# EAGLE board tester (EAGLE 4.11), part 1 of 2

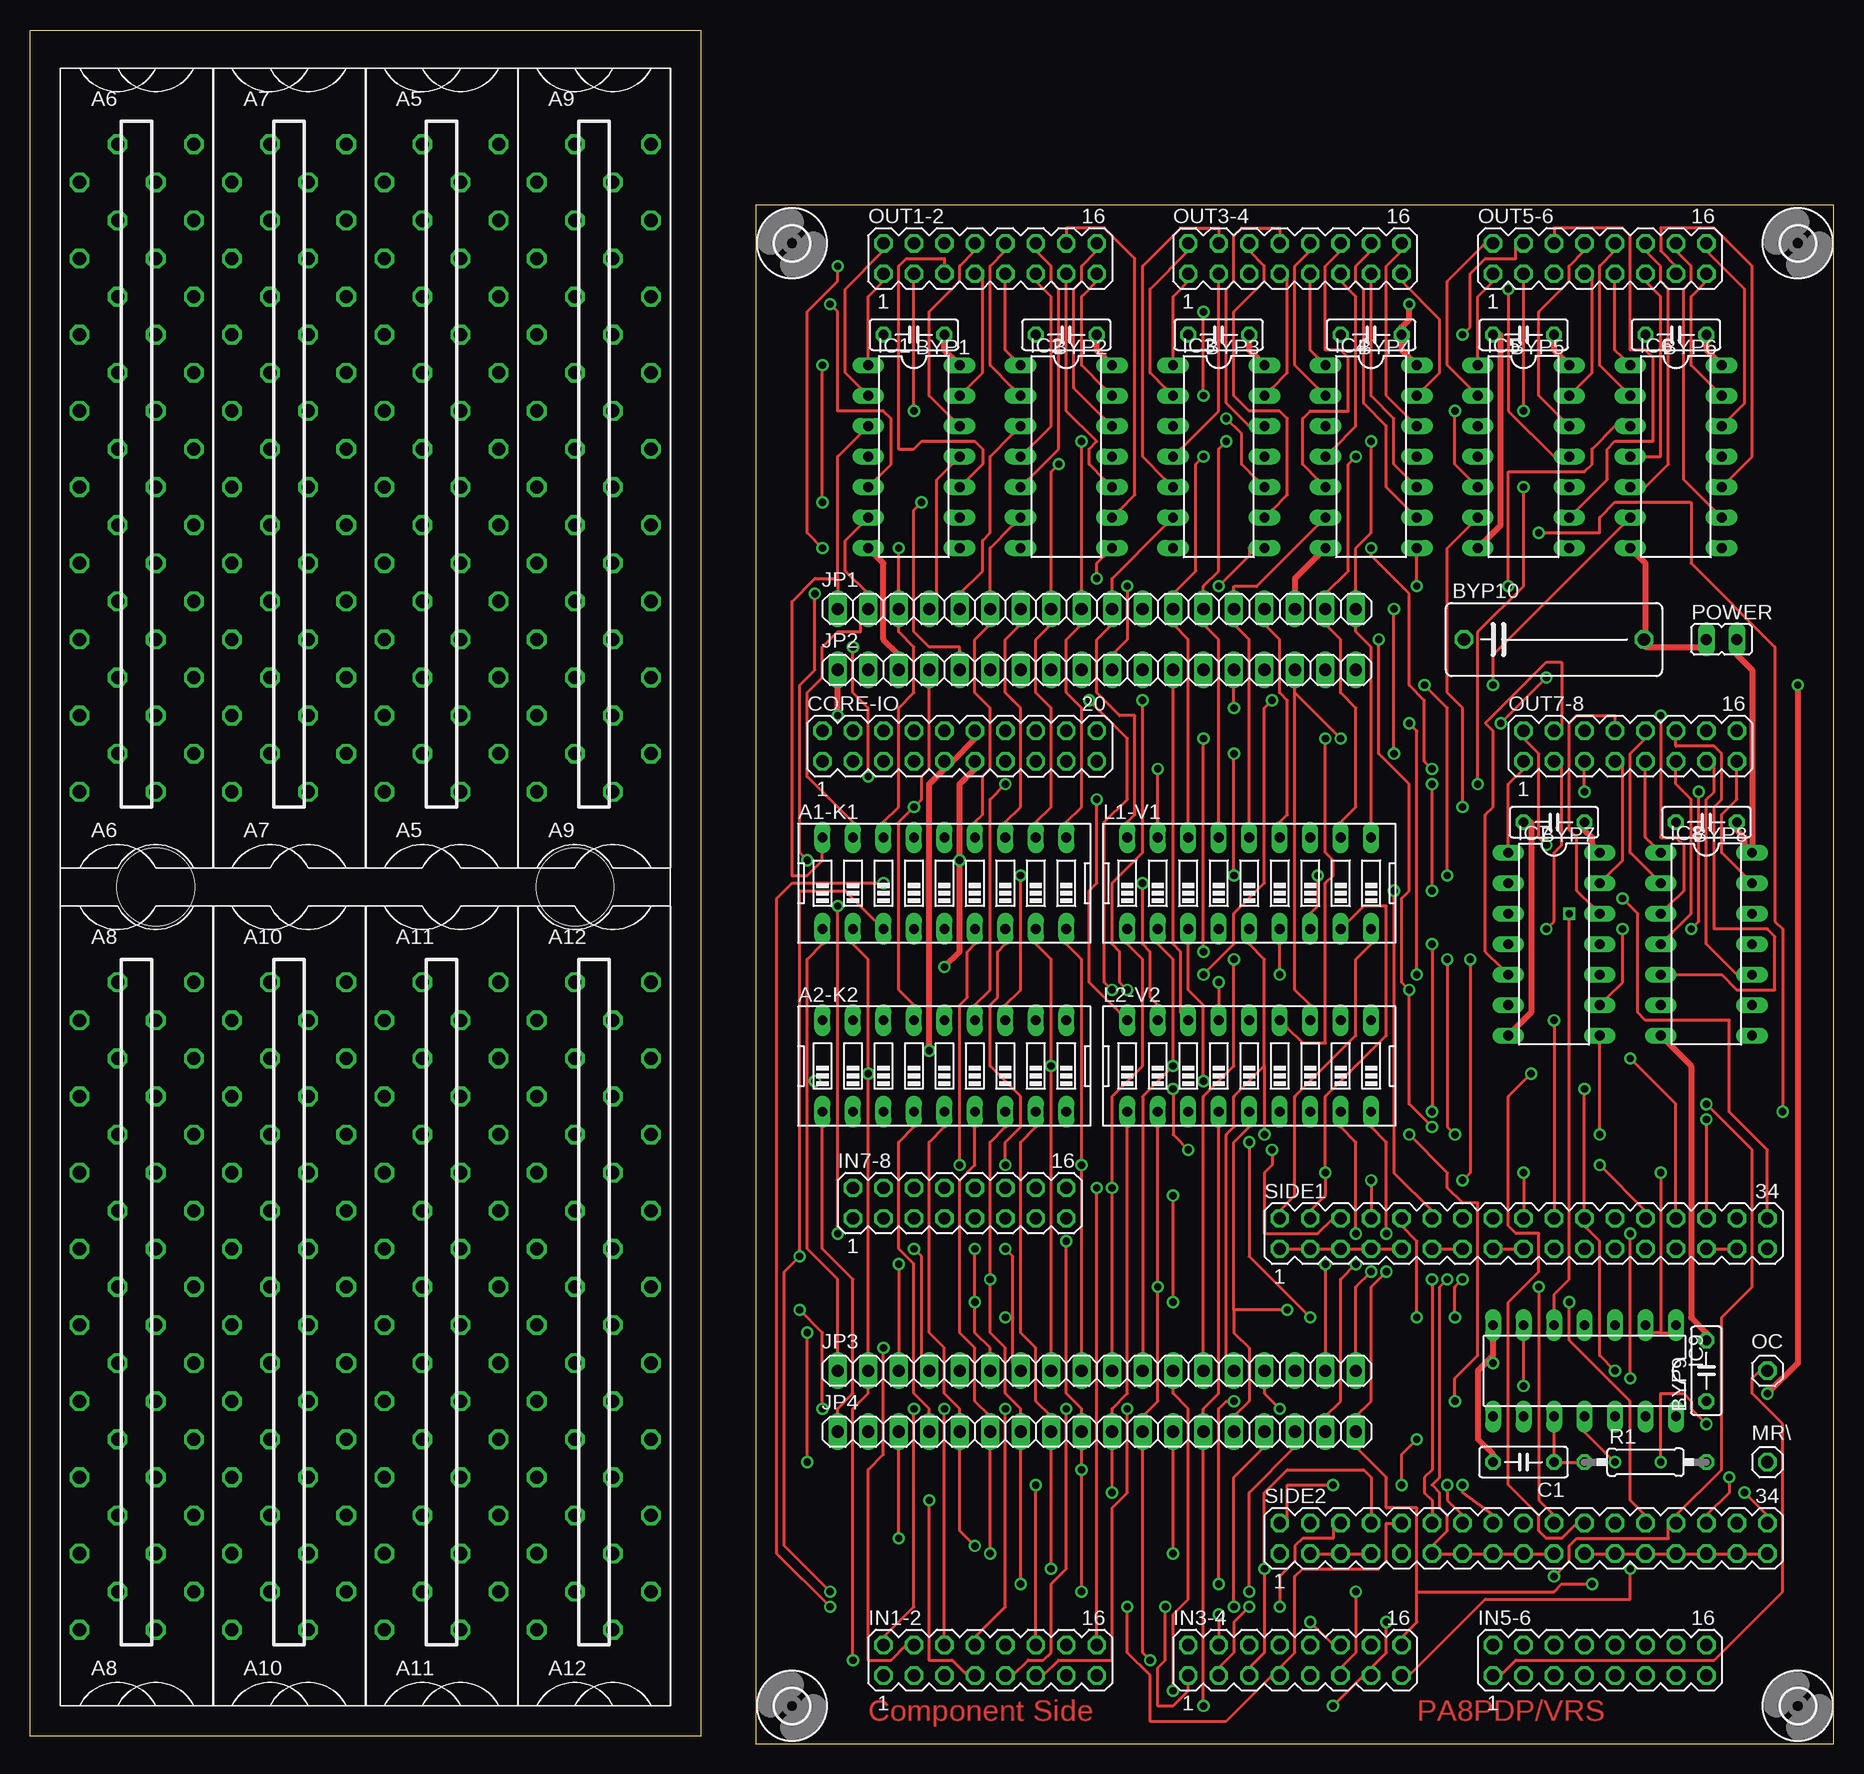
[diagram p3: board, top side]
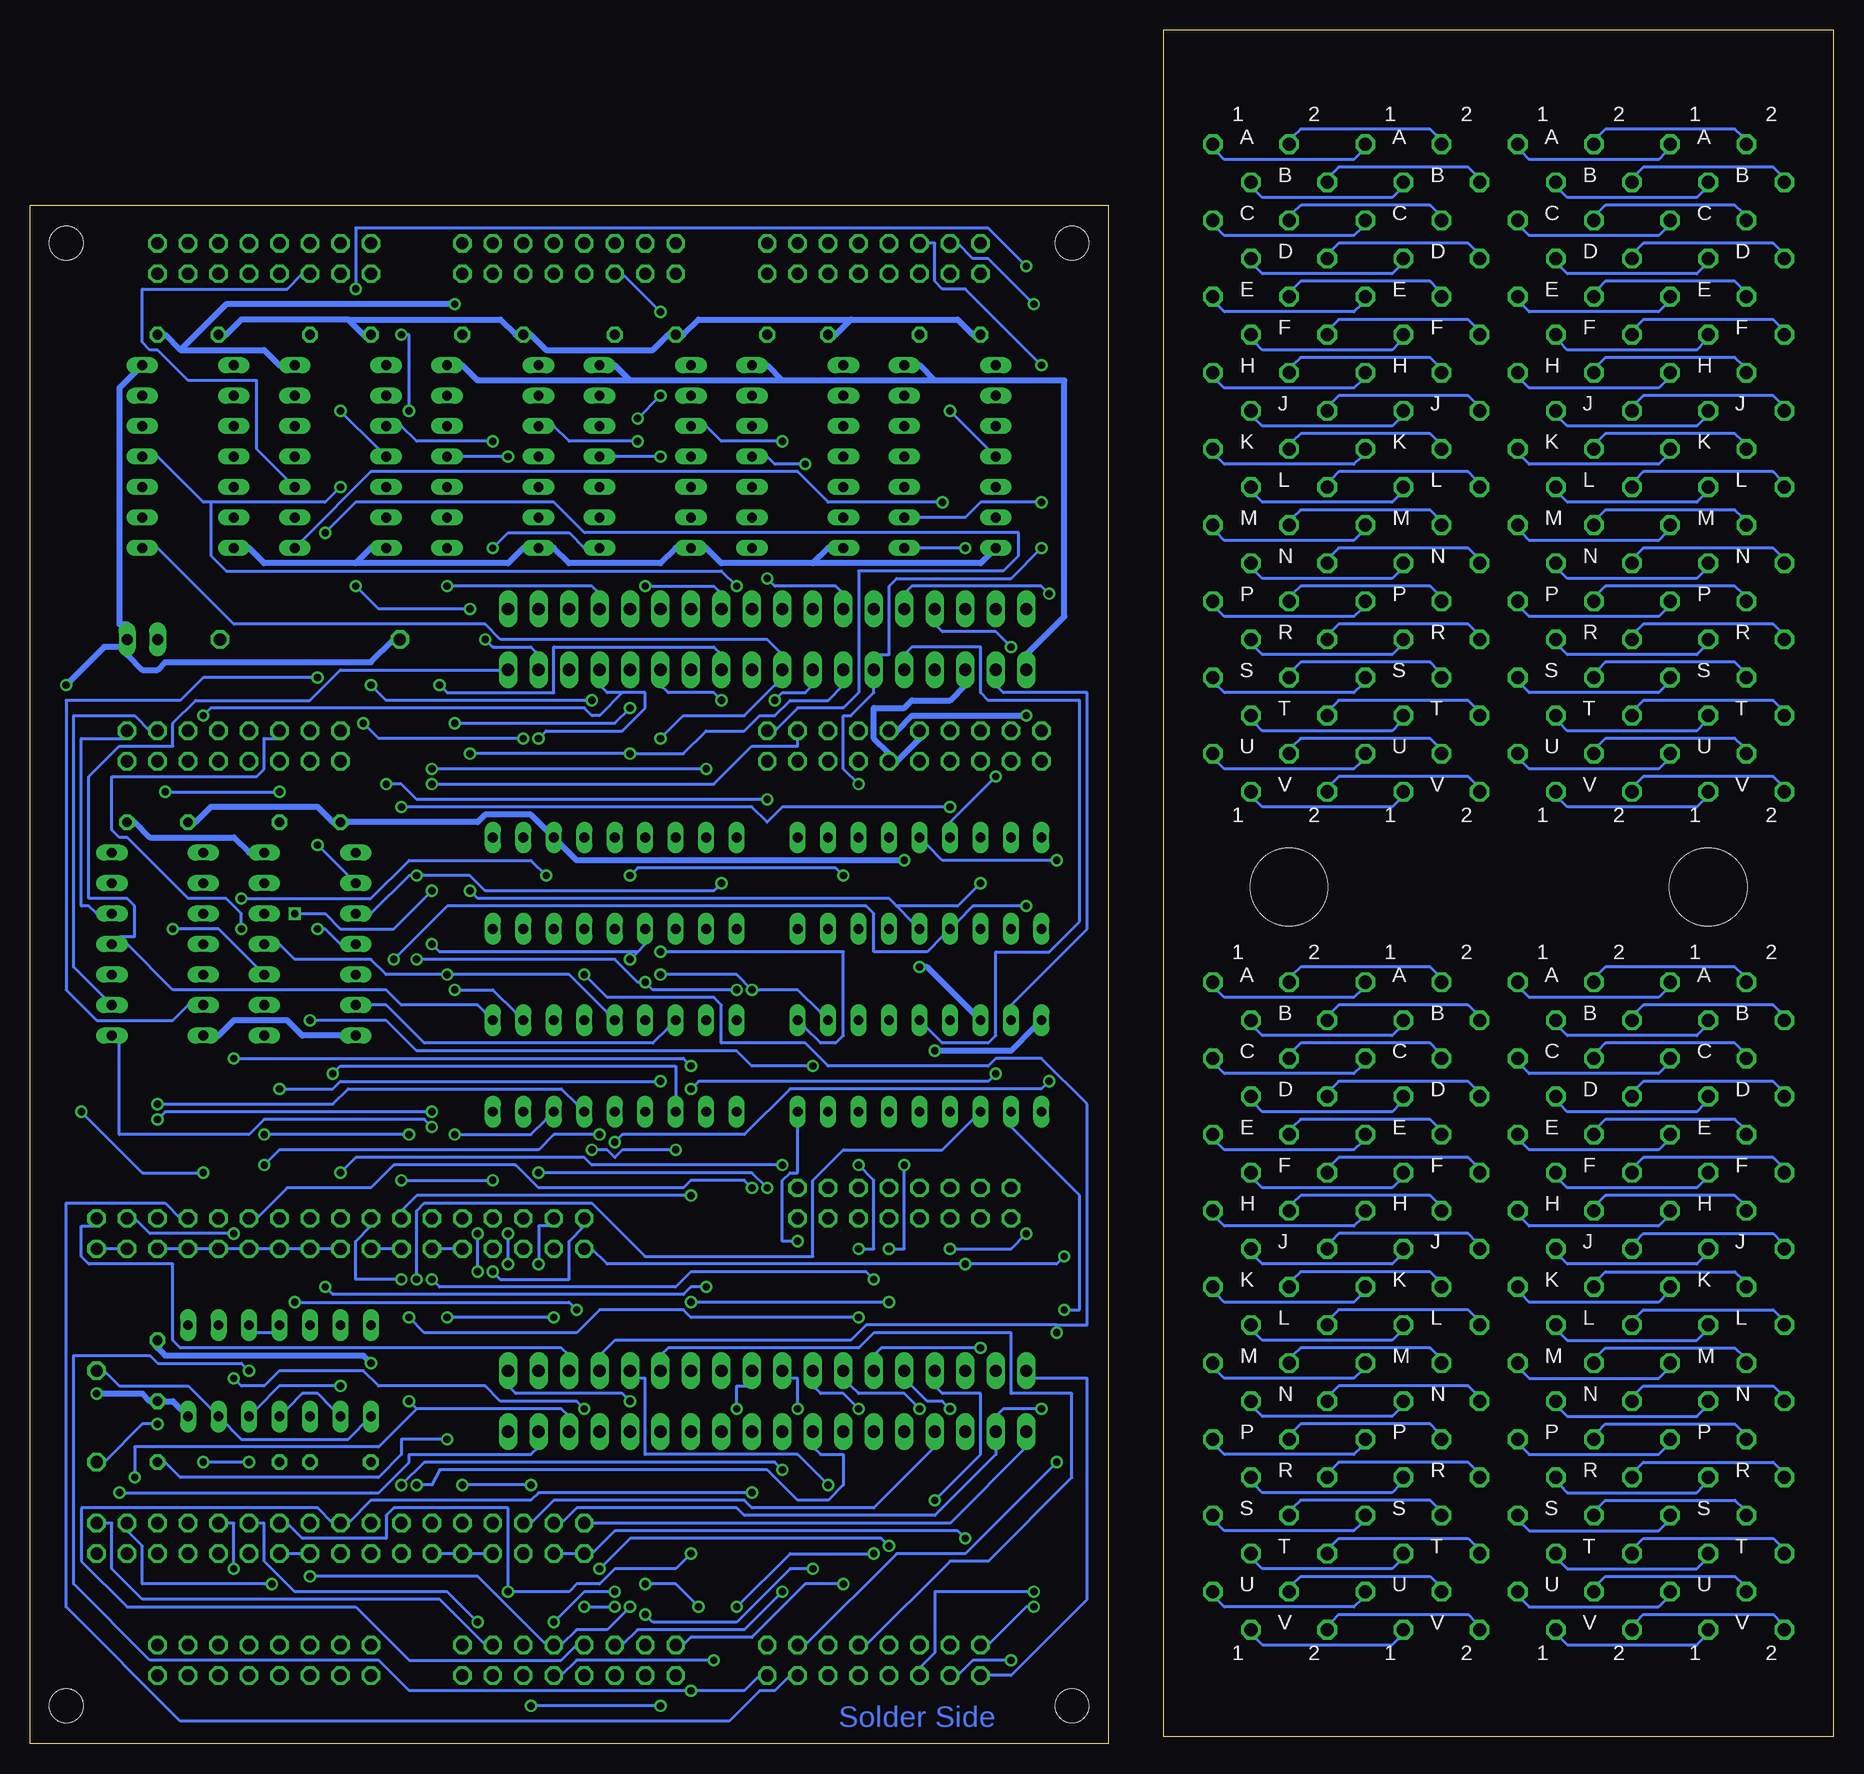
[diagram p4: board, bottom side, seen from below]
Size 150.33 x 142.86 mm. Coordinates in mm from the lower left corner, seen from the top.
Outline: 60.49,128.25 60.49,0 150.33,0 150.33,128.25 60.49,128.25
Outline: 55.88,0.62 0,0.62 0,142.86 55.88,142.86 55.88,0.62
Copper layers (1*16): Top 0.035mm / dielectric 1.5mm / Bottom 0.035mm
Design rules "olimex10mil": minimum track width 10mil, minimum drill 24mil, track to track 10mil, track to pad 10mil, pad to pad 10mil, via to via 10mil, smd to smd 10mil, copper to edge 40mil, drill to drill 10mil, minimum pad ring 10mil, minimum via ring 8mil, stop-mask expansion 0mil, vias tented up to drill 0mil, thermal gap 10mil
Net classes: 1 Power: width 0.508 mm, drill 0.254 mm, clearance 0.254 mm

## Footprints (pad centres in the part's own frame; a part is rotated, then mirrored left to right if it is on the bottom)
EDG-09 = drill 0.813 long: 1 -10.16,-3.81; 2 -7.62,-3.81; 3 -5.08,-3.81; 4 -2.54,-3.81; 5 0,-3.81; 6 2.54,-3.81; 7 5.08,-3.81; 8 7.62,-3.81; 9 10.16,-3.81; 10 10.16,3.81; 11 7.62,3.81; 12 5.08,3.81; 13 2.54,3.81; 14 0,3.81; 15 -2.54,3.81; 16 -5.08,3.81; 17 -7.62,3.81; 18 -10.16,3.81
H807 = drill 1.092 octagon: A1 4.763,28.575; A2 -1.587,28.575; B1 1.587,25.4; B2 -4.763,25.4; C1 4.763,22.225; C2 -1.587,22.225; D1 1.587,19.05; D2 -4.763,19.05; E1 4.763,15.875; E2 -1.587,15.875; F1 1.587,12.7; F2 -4.763,12.7; H1 4.763,9.525; H2 -1.587,9.525; J1 1.587,6.35; J2 -4.763,6.35; K1 4.763,3.175; K2 -1.587,3.175; L1 1.587,0; L2 -4.763,0; M1 4.763,-3.175; M2 -1.587,-3.175; N1 1.587,-6.35; N2 -4.763,-6.35; P1 4.763,-9.525; P2 -1.587,-9.525; R1 1.587,-12.7; R2 -4.763,-12.7; S1 4.763,-15.875; S2 -1.587,-15.875; T1 1.587,-19.05; T2 -4.763,-19.05; U1 4.763,-22.225; U2 -1.587,-22.225; V1 1.587,-25.4; V2 -4.763,-25.4
C050-025X075 = drill 0.813 octagon: 1 -2.54,0; 2 2.54,0
C150-064X183 = drill 1.016 octagon: 1 -7.493,0; 2 7.493,0
MA10-2 = drill 1.016 octagon: 1 -11.43,-1.27; 2 -11.43,1.27; 3 -8.89,-1.27; 4 -8.89,1.27; 5 -6.35,-1.27; 6 -6.35,1.27; 7 -3.81,-1.27; 8 -3.81,1.27; 9 -1.27,-1.27; 10 -1.27,1.27; 11 1.27,-1.27; 12 1.27,1.27; 13 3.81,-1.27; 14 3.81,1.27; 15 6.35,-1.27; 16 6.35,1.27; 17 8.89,-1.27; 18 8.89,1.27; 19 11.43,-1.27; 20 11.43,1.27
DIL14 = drill 0.813 long: 1 -7.62,-3.81; 2 -5.08,-3.81; 3 -2.54,-3.81; 4 0,-3.81; 5 2.54,-3.81; 6 5.08,-3.81; 7 7.62,-3.81; 8 7.62,3.81; 9 5.08,3.81; 10 2.54,3.81; 11 0,3.81; 12 -2.54,3.81; 13 -5.08,3.81; 14 -7.62,3.81
MA08-2 = drill 1.016 octagon: 1 -8.89,-1.27; 2 -8.89,1.27; 3 -6.35,-1.27; 4 -6.35,1.27; 5 -3.81,-1.27; 6 -3.81,1.27; 7 -1.27,-1.27; 8 -1.27,1.27; 9 1.27,-1.27; 10 1.27,1.27; 11 3.81,-1.27; 12 3.81,1.27; 13 6.35,-1.27; 14 6.35,1.27; 15 8.89,-1.27; 16 8.89,1.27
1X18 = drill 1.016 long: 1 -21.59,0; 2 -19.05,0; 3 -16.51,0; 4 -13.97,0; 5 -11.43,0; 6 -8.89,0; 7 -6.35,0; 8 -3.81,0; 9 -1.27,0; 10 1.27,0; 11 3.81,0; 12 6.35,0; 13 8.89,0; 14 11.43,0; 15 13.97,0; 16 16.51,0; 17 19.05,0; 18 21.59,0
1X01 = drill 1.016 octagon: 1 0,0
JP1 = drill 0.914 long: 1 0,-1.27; 2 0,1.27
0207/10 = drill 0.813 octagon: 1 -5.08,0; 2 5.08,0
MA17-2 = drill 1.016 octagon: 1 -20.32,-1.27; 2 -20.32,1.27; 3 -17.78,-1.27; 4 -17.78,1.27; 5 -15.24,-1.27; 6 -15.24,1.27; 7 -12.7,-1.27; 8 -12.7,1.27; 9 -10.16,-1.27; 10 -10.16,1.27; 11 -7.62,-1.27; 12 -7.62,1.27; 13 -5.08,-1.27; 14 -5.08,1.27; 15 -2.54,-1.27; 16 -2.54,1.27; 17 0,-1.27; 18 0,1.27; 19 2.54,-1.27; 20 2.54,1.27; 21 5.08,-1.27; 22 5.08,1.27; 23 7.62,-1.27; 24 7.62,1.27; 25 10.16,-1.27; 26 10.16,1.27; 27 12.7,-1.27; 28 12.7,1.27; 29 15.24,-1.27; 30 15.24,1.27; 31 17.78,-1.27; 32 17.78,1.27; 33 20.32,-1.27; 34 20.32,1.27
2,8 = hole 2.8: 0,0
CBLOCK = hole 6.452: 7.938,68.263; 42.862,68.263

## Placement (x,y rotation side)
A1-K1  A1-K1  [EDG-09]  76.2,71.74 0 top
A2-K2  A2-K2  [EDG-09]  76.2,56.5 0 top
A5  [H807]  34.29,104.76 0 top
A6  [H807]  8.89,104.76 0 top
A7  [H807]  21.59,104.76 0 top
A8  [H807]  8.89,34.91 0 top
A9  [H807]  46.99,104.76 0 top
A10  [H807]  21.59,34.91 0 top
A11  [H807]  34.29,34.91 0 top
A12  [H807]  46.99,34.91 0 top
BYP1  0.1uf  [C050-025X075]  73.66,117.46 180 top
BYP2  0.1uf  [C050-025X075]  86.36,117.46 180 top
BYP3  0.1uf  [C050-025X075]  99.06,117.46 180 top
BYP4  0.1uf  [C050-025X075]  111.76,117.46 180 top
BYP5  0.1uf  [C050-025X075]  124.46,117.46 180 top
BYP6  0.1uf  [C050-025X075]  137.16,117.46 180 top
BYP7  0.1uf  [C050-025X075]  127,76.82 180 top
BYP8  0.1uf  [C050-025X075]  139.7,76.82 180 top
BYP9  0.1uf  [C050-025X075]  139.7,31.1 90 top
BYP10  100uf 25V  [C150-064X183]  127,92.06 0 top
C1  0.1uf  [C050-025X075]  124.46,23.48 180 top
CORE-IO  [MA10-2]  77.47,83.17 0 top
IC1  74LS125N  [DIL14]  73.66,107.3 270 top
IC2  74LS125N  [DIL14]  86.36,107.3 270 top
IC3  74LS125N  [DIL14]  99.06,107.3 270 top
IC4  74LS125N  [DIL14]  111.76,107.3 270 top
IC5  74LS125N  [DIL14]  124.46,107.3 270 top
IC6  74LS125N  [DIL14]  137.16,107.3 270 top
IC7  74LS125N  [DIL14]  127,66.66 270 top
IC8  74LS125N  [DIL14]  139.7,66.66 270 top
IC9  74LS00N  [DIL14]  129.54,31.1 180 top
IN1-2  [MA08-2]  80.01,6.97 0 top
IN3-4  [MA08-2]  105.41,6.97 0 top
IN5-6  [MA08-2]  130.81,6.97 0 top
IN7-8  [MA08-2]  77.47,45.07 0 top
JP1  [1X18]  88.9,94.6 0 top
JP2  [1X18]  88.9,89.52 0 top
JP3  [1X18]  88.9,31.1 0 top
JP4  [1X18]  88.9,26.02 0 top
L1-V1  L1-V1  [EDG-09]  101.6,71.74 0 top
L2-V2  L2-V2  [EDG-09]  101.6,56.5 0 top
MR\  MR\  [1X01]  144.78,23.48 0 top
OC  OC  [1X01]  144.78,31.1 0 top
OUT1-2  [MA08-2]  80.01,123.81 0 top
OUT3-4  [MA08-2]  105.41,123.81 0 top
OUT5-6  [MA08-2]  130.81,123.81 0 top
OUT7-8  [MA08-2]  133.35,83.17 0 top
POWER  POWER  [JP1]  140.97,92.06 270 top
R1  1K  [0207/10]  134.62,23.48 0 top
SIDE1  [MA17-2]  124.46,42.53 0 top
SIDE2  [MA17-2]  124.46,17.13 0 top
U$1  [2,8]  63.5,3.16 270 top
U$2  [2,8]  147.32,3.16 270 top
U$3  [2,8]  147.32,125.08 270 top
U$4  [2,8]  63.5,125.08 270 top
U$5  [CBLOCK]  2.54,3.16 0 top

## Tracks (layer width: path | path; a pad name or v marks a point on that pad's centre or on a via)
A1  (via drill 0.61)
  Top 0.254: 64.77,55.23 64.77,41.26 67.31,38.72 67.31,32.37 JP3.1 | 64.77,55.23 64.77,65.39 66.04,66.66 A1-K1.1 | v115.57,35.55 115.57,41.89 114.3,43.16 SIDE1.10 | v106.68,35.55 101.6,40.62 v101.6,50.15 | 64.77,55.23 v65.41,55.23
  Bottom 0.254: IN1-2.1 70.48,5.7 68.58,5.7 62.23,12.05 62.23,30.46 66.67,30.46 JP3.1 | v106.68,35.55 v115.57,35.55 | v101.6,50.15 100.97,50.78 90.81,50.78 87,54.59 66.04,54.59 v65.41,55.23
A2  (via drill 0.61)
  Top 0.254: A2-K2.1 66.04,51.42 66.04,41.26 68.58,38.72 68.58,29.2 67.31,27.92 67.31,27.29 JP4.1 | v115.57,25.38 114.3,24.11 v114.3,21.57 | v108.59,21.57 104.78,21.57 104.78,18.4 SIDE2.2
  Bottom 0.254: SIDE2.2 103.5,18.4 73.66,18.4 67.31,24.75 JP4.1 | v115.57,25.38 119.38,25.38 119.38,24.11 121.28,22.21 137.8,22.21 139.06,23.48 R1.2 | v108.59,21.57 v114.3,21.57
B1  (via drill 0.61)
  Top 0.254: A1-K1.2 68.58,66.66 69.85,65.39 v69.85,55.87 69.85,32.37 JP3.2 69.85,29.83 69.85,29.2 68.58,27.92 v68.58,6.97 | v103.5,49.52 103.5,48.24 102.87,47.61 102.87,42.53 107.31,42.53 108.59,43.8 SIDE1.6 | v96.52,49.52 95.25,50.78 v95.25,54.59
  Bottom 0.254: v68.58,6.97 71.75,6.97 73.03,5.7 IN1-2.3 | v96.52,49.52 100.97,49.52 101.6,48.88 102.23,49.52 v103.5,49.52 | v95.25,54.59 94.62,55.23 70.48,55.23 v69.85,55.87
B2  (via drill 0.61)
  Top 0.254: v64.14,36.18 66.04,34.27 v66.04,27.92
  Bottom 0.254: v64.14,36.18 62.87,36.18 62.87,45.7 68.58,51.42 A2-K2.2 | v66.04,27.92 69.22,27.92 69.85,27.29 JP4.2 69.85,24.75 69.85,24.11 74.93,19.04 90.81,19.04 91.44,19.67 104.78,19.67 106.05,18.4 SIDE2.4
C1  (via drill 0.61)
  Top 0.254: A1-K1.3 70.48,68.57 67.95,71.11 64.14,71.11 v64.14,40.62 62.87,39.35 62.87,16.49 v66.67,12.68 | v72.39,39.99 72.39,32.37 JP3.3 | SIDE1.1 104.78,41.26 106.05,41.26 SIDE1.3 107.31,41.26 108.59,41.26 SIDE1.5 109.86,41.26 111.12,41.26 SIDE1.7 112.4,41.26 113.66,41.26 SIDE1.9 | SIDE1.13 118.75,41.26 117.47,41.26 SIDE1.11 | SIDE1.17 123.83,41.26 122.56,41.26 SIDE1.15 | SIDE1.31 141.61,41.26 140.34,41.26 SIDE1.29
  Bottom 0.254: v64.14,40.62 64.77,39.99 v72.39,39.99 102.23,39.99 103.5,41.26 SIDE1.1 | v66.67,12.68 74.93,12.68 74.93,7.6 76.2,6.33 IN1-2.5 | SIDE1.11 116.2,41.26 114.94,41.26 SIDE1.9 | SIDE1.15 121.28,41.26 120.02,41.26 SIDE1.13 | SIDE1.17 125.09,41.26 126.36,41.26 SIDE1.19 127.64,41.26 128.91,41.26 SIDE1.21 130.18,41.26 131.44,41.26 SIDE1.23 132.72,41.26 133.99,41.26 SIDE1.25 135.25,41.26 136.53,41.26 SIDE1.27 137.8,41.26 139.06,41.26 SIDE1.29 | SIDE1.33 144.14,41.26 142.88,41.26 SIDE1.31
C2  (via drill 0.61)
  Top 0.254: SIDE2.3 107.31,15.86 108.59,15.86 SIDE2.5 109.86,15.86 111.12,15.86 SIDE2.7 | v72.39,17.13 72.39,24.75 JP4.3 | v118.11,38.72 117.47,38.09 117.47,22.21 116.84,21.57 117.47,20.94 117.47,19.67 118.11,19.04 118.11,17.77 116.84,16.49 SIDE2.11 117.47,15.86 118.75,15.86 SIDE2.13 120.02,15.86 121.28,15.86 SIDE2.15 122.56,15.86 123.83,15.86 SIDE2.17 125.09,15.86 126.36,15.86 SIDE2.19 | SIDE2.21 130.18,15.86 131.44,15.86 SIDE2.23 132.72,15.86 133.99,15.86 SIDE2.25 135.25,15.86 136.53,15.86 SIDE2.27 137.8,15.86 139.06,15.86 SIDE2.29 140.34,15.86 141.61,15.86 SIDE2.31 142.88,15.86 144.14,15.86 SIDE2.33
  Bottom 0.254: SIDE2.3 106.05,15.86 104.78,15.86 SIDE2.1 103.5,15.86 101.6,17.77 73.03,17.77 v72.39,17.13 | SIDE2.7 112.4,15.86 113.66,15.86 SIDE2.9 114.94,15.86 116.2,15.86 SIDE2.11 | v118.11,38.72 118.11,44.44 117.47,45.07 103.5,45.07 99.06,40.62 85.09,40.62 85.09,46.98 82.55,49.52 74.3,49.52 71.75,52.05 A2-K2.3 | SIDE2.21 128.91,15.86 127.64,15.86 SIDE2.19
D1  (via drill 0.61)
  Top 0.254: v67.31,42.53 v67.31,69.84 | v73.66,41.26 74.3,40.62 74.3,31.73 JP3.4 | v74.93,20.3 74.93,6.97 76.84,6.97 78.11,5.7 IN1-2.7 | v111.76,46.98 111.76,44.44 SIDE1.8 | v119.38,46.98 120.02,47.61 v120.02,65.39
  Bottom 0.254: v67.31,69.84 71.75,69.84 73.03,68.57 A1-K1.4 74.3,67.3 75.56,66.03 80.01,66.03 80.01,69.2 80.65,69.84 115.57,69.84 v120.02,65.39 | v67.31,42.53 68.58,41.26 v73.66,41.26 | v74.93,20.3 71.12,24.11 71.12,29.2 74.3,29.2 74.93,29.83 JP3.4 | v119.38,46.98 v111.76,46.98
D2  (via drill 0.61)
  Top 0.254: v101.6,11.41 100.33,10.14 100.33,7.6 99.06,6.33 IN3-4.3 | v104.14,11.41 104.14,13.95 105.41,15.22 105.41,16.49 106.05,17.13 108.59,17.13 108.59,18.4 SIDE2.6 | A2-K2.4 73.66,51.42 72.39,50.15 72.39,41.26 73.66,39.99 73.66,29.2 74.93,27.92 74.93,27.29 JP4.4
  Bottom 0.254: v104.14,11.41 v101.6,11.41 | SIDE2.6 108.59,18.4 106.68,20.3 90.81,20.3 90.17,19.67 80.01,19.67 74.93,24.75 JP4.4
E1  (via drill 0.61)
  Top 0.254: v73.66,27.92 73.66,11.41 71.12,8.88 IN1-2.2 | v113.66,71.11 113.66,47.61 116.84,44.44 SIDE1.12 | v66.67,11.41 62.23,15.86 62.23,70.47 63.5,71.74 v71.12,71.74
  Bottom 0.254: v73.66,27.92 74.3,28.56 75.56,28.56 76.84,29.83 77.47,29.83 JP3.5 | 78.11,69.84 78.74,70.47 113.03,70.47 v113.66,71.11 | 78.11,69.84 76.84,68.57 A1-K1.5 | v66.67,11.41 67.31,11.41 70.48,8.24 IN1-2.2 | v71.12,71.74 73.03,69.84 78.11,69.84
E2  (via drill 0.61)
  Top 0.254: IN3-4.5 101.6,6.33 102.87,7.6 v102.87,14.59 102.87,20.3 102.87,20.94 104.78,22.84 111.12,22.84 111.76,22.21 111.76,19.04 SIDE2.8 | A2-K2.5 76.2,51.42 74.93,50.15 74.93,34.27 76.2,33.01 76.2,29.2 77.47,27.92 77.47,27.29 JP4.5 77.47,24.75 77.47,17.77 v78.74,16.49
  Bottom 0.254: v102.87,14.59 100.33,17.13 79.38,17.13 v78.74,16.49
F1  (via drill 0.61)
  Top 0.254: v77.47,48.24 77.47,61.58 78.11,62.21 78.11,66.03 78.74,66.66 A1-K1.6 | v78.74,41.26 v78.74,36.81 78.74,34.27 80.01,33.01 80.01,32.37 JP3.6 | v71.12,33.01 71.12,24.11 69.85,22.84 69.85,6.97 71.75,6.97 73.03,8.24 IN1-2.4 | v95.25,36.81 v95.25,45.7
  Bottom 0.254: v77.47,48.24 77.47,41.26 v78.74,41.26 | v71.12,33.01 79.38,33.01 80.01,32.37 JP3.6 | v95.25,45.7 118.11,45.7 119.38,44.44 SIDE1.14 | v78.74,36.81 v95.25,36.81
F2  (via drill 0.61)
  Top 0.254: SIDE2.10 113.66,18.4 113.03,18.4 113.03,15.22 112.4,14.59 106.05,14.59 105.41,13.95 105.41,7.6 104.14,6.33 IN3-4.7 103.5,5.7 99.69,1.89 93.34,1.89 93.34,5.7 91.44,7.6 v91.44,11.41 | A2-K2.6 78.74,51.42 78.74,48.24 77.47,46.98 77.47,34.27 78.74,33.01 78.74,28.56 80.01,27.29 JP4.6 80.01,24.75 v80.01,15.86
  Bottom 0.254: v91.44,11.41 87,15.86 v80.01,15.86
GND  (via drill 0.61)
  Top 0.508: 121.28,31.73 121.92,32.37 121.92,33.64 IC9.7 | 121.28,31.73 120.65,31.1 120.65,25.38 121.92,24.11 C1.2 | IC7.7 123.83,59.68 125.09,60.95 125.09,76.82 BYP7.2 | BYP9.2 139.7,34.27 138.43,35.55 138.43,56.5 136.53,58.41 IC8.7 | v121.92,31.73 121.28,31.73 | v76.2,64.76 77.47,66.03 v77.47,73.65 77.47,80 78.74,81.27 CORE-IO.11 | IC1.7 70.48,99.05 71.12,98.41 71.12,92.06 72.39,90.79 JP2.3 | IC4.7 107.31,99.05 105.41,97.14 105.41,95.87 JP1.16 | IC6.7 133.99,99.05 134.62,98.41 134.62,92.7 BYP10.2 134.62,91.43 139.06,91.43 POWER.1 | IC5.7 121.28,100.32 122.56,101.59 122.56,117.46 BYP5.2
  Bottom 0.508: L1-V1.12 107.31,76.19 | IC8.7 134.62,59.04 133.35,60.31 128.91,60.31 127.64,59.04 124.46,59.04 IC7.7 | BYP8.2 136.53,76.82 135.25,78.09 126.36,78.09 125.09,76.82 BYP7.2 123.83,76.82 113.03,76.82 112.4,77.46 108.59,77.46 107.31,76.19 | v121.92,31.73 122.56,32.37 139.06,32.37 139.7,33.01 BYP9.2 | v76.2,64.76 75.56,64.76 71.75,60.95 A2-K2.16 | CORE-IO.10 76.2,83.81 78.11,81.9 CORE-IO.11 78.74,82.54 80.01,83.81 80.01,86.35 77.47,86.35 76.84,86.98 73.66,86.98 72.39,88.25 JP2.3 | 85.09,98.41 83.82,99.68 IC2.7 | 85.09,98.41 92.71,98.41 93.98,99.68 IC3.7 96.52,99.68 97.79,98.41 105.41,98.41 106.68,99.68 IC4.7 109.22,99.68 110.49,98.41 123.19,98.41 | 85.09,98.41 71.12,98.41 70.48,99.05 IC1.7 | 81.92,118.73 73.03,118.73 71.75,117.46 BYP1.2 | 81.92,118.73 83.19,117.46 BYP2.2 | 81.92,118.73 94.62,118.73 95.89,117.46 BYP3.2 97.16,117.46 98.43,116.19 107.31,116.19 108.59,117.46 BYP4.2 109.86,117.46 111.12,118.73 123.83,118.73 | 123.83,118.73 132.72,118.73 133.99,117.46 BYP6.2 | 123.83,118.73 122.56,117.46 BYP5.2 | 123.19,98.41 130.81,98.41 132.08,99.68 IC6.7 | 123.19,98.41 121.92,99.68 IC5.7 | v77.47,73.65 104.78,73.65 106.05,74.92 L1-V1.12 | L1-V1.12 107.31,76.19
H1  (via drill 0.61)
  Top 0.254: v81.28,48.24 81.28,50.15 82.55,51.42 82.55,53.96 80.01,56.5 80.01,61.58 80.65,62.21 80.65,66.03 81.28,66.66 A1-K1.7 | v81.28,41.26 81.92,40.62 81.92,35.55 | 81.92,35.55 81.92,31.73 JP3.7 | v76.2,27.92 76.2,8.88 IN1-2.6 | v119.38,38.72 118.75,38.09 v118.75,35.55 | 81.92,35.55 v81.28,35.55
  Bottom 0.254: v81.28,48.24 80.01,46.98 80.01,41.26 v81.28,41.26 | v76.2,27.92 77.47,29.2 81.28,29.2 81.92,29.83 82.55,29.83 JP3.7 | v119.38,38.72 123.19,38.72 123.19,41.89 121.92,43.16 SIDE1.16 | v118.75,35.55 117.47,34.27 104.78,34.27 102.87,36.18 95.89,36.18 95.25,35.55 v81.28,35.55
H2  (via drill 0.61)
  Top 0.254: A2-K2.7 81.28,51.42 80.01,50.15 v80.01,38.72 80.01,34.27 81.28,33.01 81.28,29.2 82.55,27.92 82.55,27.29 JP4.7 82.55,24.75 v82.55,13.32 | v116.84,38.72 116.84,22.84 116.2,22.21 116.2,20.94 116.84,20.3 116.84,19.04 SIDE2.12
  Bottom 0.254: v82.55,13.32 85.72,13.32 90.17,8.88 95.25,8.88 95.89,8.24 IN3-4.2 | v116.84,38.72 116.2,38.09 96.52,38.09 95.25,39.35 80.65,39.35 v80.01,38.72
J1  (via drill 0.61)
  Top 0.254: A1-K1.8 83.82,66.66 85.09,65.39 v85.09,56.5 85.09,32.37 JP3.8 | v81.28,27.92 81.28,11.41 78.74,8.88 IN1-2.8 | v127,60.31 127,44.44 SIDE1.20
  Bottom 0.254: v81.28,27.92 82.55,29.2 84.45,29.2 85.09,29.83 JP3.8 | v127,60.31 120.65,60.31 118.11,57.77 91.44,57.77 90.17,56.5 v85.09,56.5
J2  (via drill 0.61)
  Top 0.254: A2-K2.8 83.82,51.42 82.55,50.15 82.55,34.27 83.82,33.01 83.82,28.56 85.09,27.29 JP4.8 85.09,24.75 v85.09,14.59 | v99.06,10.78 99.06,8.88 IN3-4.4 | v118.11,21.57 118.11,20.3 119.38,19.04 SIDE2.14
  Bottom 0.254: v99.06,10.78 98.43,10.14 91.44,10.14 87,14.59 v85.09,14.59 | v118.11,21.57 116.84,21.57 116.2,22.84 88.9,22.84 86.36,20.3 83.82,20.3 82.55,21.57 82.55,24.11 84.45,24.11 85.09,24.75 JP4.8
K1  (via drill 0.61)
  Top 0.254: v86.36,27.92 86.36,14.59 85.09,13.32 85.09,7.6 84.45,6.97 83.19,6.97 81.92,5.7 IN1-2.9 | A1-K1.9 86.36,66.66 87.63,65.39 v87.63,48.24 87.63,32.37 JP3.9 | v124.46,47.61 124.46,44.44 SIDE1.18
  Bottom 0.254: v86.36,27.92 86.36,30.46 87,30.46 JP3.9 | v124.46,47.61 123.19,48.88 104.14,48.88 103.5,48.24 v87.63,48.24
K2  (via drill 0.61)
  Top 0.254: v86.36,41.89 86.36,29.2 87.63,27.92 87.63,27.29 JP4.9 87.63,24.75 v87.63,22.84 v87.63,12.68 | v119.38,21.57 119.38,20.94 121.92,19.04 SIDE2.16
  Bottom 0.254: v86.36,41.89 87.63,41.89 87.63,46.98 87,47.61 86.36,47.61 86.36,51.42 A2-K2.9 | v87.63,12.68 90.81,9.51 99.69,9.51 100.97,8.24 IN3-4.6 | v87.63,22.84 88.27,23.48 117.47,23.48 v119.38,21.57
L1  (via drill 0.61)
  Top 0.254: L1-V1.1 91.44,66.66 92.71,65.39 92.71,56.5 90.17,53.96 v90.17,46.34 90.17,32.37 JP3.10 | v91.44,27.92 91.44,20.94 90.17,19.67 90.17,6.97 85.72,6.97 84.45,5.7 IN1-2.11
  Bottom 0.254: v91.44,27.92 91.44,29.83 90.17,29.83 JP3.10 | v90.17,46.34 90.81,46.98 95.25,46.98 95.89,46.34 107.95,46.34 109.86,48.24 120.02,48.24 121.92,46.34 128.91,46.34 131.44,43.8 SIDE1.24
L2  (via drill 0.61)
  Top 0.254: L2-V2.1 91.44,29.2 90.17,27.92 JP4.10 v90.17,20.94
  Bottom 0.254: IN3-4.8 104.78,8.24 106.05,6.97 118.75,6.97 123.19,11.41 142.24,11.41 146.05,15.22 146.05,19.67 126.36,19.67 125.09,18.4 SIDE2.18 123.83,18.4 121.92,20.3 108.59,20.3 107.95,20.94 v90.17,20.94
M1  (via drill 0.61)
  Top 0.254: L1-V1.2 93.98,66.66 95.25,65.39 v95.25,56.5 92.71,53.96 92.71,32.37 JP3.11 | v133.35,57.13 137.16,53.32 137.16,44.44 SIDE1.28
  Bottom 0.254: IN1-2.13 87,5.7 88.27,4.43 89.53,4.43 92.08,1.89 137.8,1.89 147.32,11.41 147.32,45.07 139.06,45.07 137.8,43.8 SIDE1.28 | v95.25,56.5 95.89,57.13 v133.35,57.13
M2  (via drill 0.61)
  Top 0.254: L2-V2.2 93.98,51.42 v93.98,38.09 93.98,28.56 92.71,27.29 JP4.11 92.71,24.75 92.71,7.6 v93.34,6.97 | v125.73,38.09 125.73,20.3 127,19.04 SIDE2.20
  Bottom 0.254: v93.34,6.97 104.78,6.97 106.05,5.7 IN3-4.9 | v125.73,38.09 125.09,37.45 95.89,37.45 95.25,38.09 v93.98,38.09
MR\  (via drill 0.61)
  Top 0.254: v139.7,26.65 138.43,27.92 138.43,28.56 137.8,29.2 135.89,29.2 v135.89,23.48 | v132.08,23.48 129.54,26.02 IC9.11
  Bottom 0.254: IC9.9 125.09,27.92 126.36,29.2 127.64,29.2 128.91,27.92 IC9.11 | v139.7,26.65 140.97,26.65 144.14,23.48 MR\.1 | v132.08,23.48 v135.89,23.48
N1  (via drill 0.61)
  Top 0.254: v95.25,4.43 95.25,10.78 96.52,12.05 96.52,27.92 95.25,29.2 95.25,29.83 JP3.12 | v97.79,55.23 97.79,61.58 96.52,62.85 96.52,66.66 L1-V1.3 | v129.54,54.59 129.54,53.32 129.54,44.44 SIDE1.22 129.54,43.16 130.81,41.89 130.81,32.37 v132.08,31.1
  Bottom 0.254: IN1-2.15 89.53,5.7 90.81,4.43 v95.25,4.43 118.75,4.43 121.28,6.97 140.34,6.97 146.69,13.32 146.69,32.37 140.34,32.37 139.7,31.73 132.72,31.73 v132.08,31.1 | v97.79,55.23 124.46,55.23 125.09,54.59 v129.54,54.59
N2  (via drill 0.61)
  Top 0.254: v125.09,55.87 123.19,53.96 123.19,43.16 123.83,42.53 125.73,42.53 125.73,39.35 123.19,36.81 123.19,21.57 125.73,19.04 125.73,17.77 126.36,17.13 127.64,17.13 128.91,18.4 SIDE2.22 | v110.49,12.68 110.49,7.6 109.22,6.33 IN3-4.11 | v95.25,15.86 95.25,24.75 JP4.12
  Bottom 0.254: v125.09,55.87 124.46,56.5 96.52,56.5 96.52,53.96 L2-V2.3 | SIDE2.22 128.91,18.4 127.64,17.13 120.65,17.13 120.65,19.04 120.02,19.67 110.49,19.67 v110.49,12.68 105.41,12.68 104.78,13.32 102.87,13.32 101.6,14.59 96.52,14.59 v95.25,15.86
N$1  (via drill 0.61)
  Top 0.254: v124.46,29.83 124.46,33.64 IC9.6
  Bottom 0.254: v124.46,29.83 129.54,29.83 131.44,27.92 IC9.12
N$2
  Bottom 0.254: IC9.4 130.18,34.27 131.44,34.27 IC9.3
N$5
  Top 0.254: R1.1 128.91,23.48 127.64,23.48 C1.1 127,24.11 127,26.02 IC9.10
N$26
  Bottom 0.254: A5.L1 36.2,104.12 36.83,103.49 47.62,103.49 48.26,104.12 A9.L1
N$33
  Bottom 0.254: A5.L2 29.85,105.4 30.48,106.03 41.28,106.03 41.91,105.4 A9.L2
N$34
  Bottom 0.254: A5.M1 39.37,100.95 40.01,100.32 50.8,100.32 51.44,100.95 A9.M1
N$35
  Bottom 0.254: A5.M2 33.02,102.22 33.66,102.86 44.45,102.86 45.09,102.22 A9.M2
N$36
  Bottom 0.254: A5.N1 36.2,97.78 36.83,97.14 47.62,97.14 48.26,97.78 A9.N1
N$49
  Bottom 0.254: A5.N2 29.85,99.05 30.48,99.68 41.28,99.68 41.91,99.05 A9.N2
N$50
  Bottom 0.254: A5.P1 39.37,94.6 40.01,93.97 50.8,93.97 51.44,94.6 A9.P1
N$51
  Bottom 0.254: A5.P2 33.02,95.87 33.66,96.51 44.45,96.51 45.09,95.87 A9.P2
N$52
  Bottom 0.254: A5.R1 36.2,91.43 36.83,90.79 47.62,90.79 48.26,91.43 A9.R1
N$53
  Top 0.254: IC1.1 69.85,115.56 69.85,120.64 71.12,121.91 OUT1-2.1
N$54  (via drill 0.61)
  Top 0.254: v73.66,111.11 73.66,121.91 OUT1-2.3
  Bottom 0.254: v73.66,111.11 70.48,107.94 IC1.4
N$55
  Top 0.254: IC1.10 78.11,105.4 79.38,106.67 79.38,107.94 78.74,108.57 74.3,108.57 73.66,107.94 72.39,107.94 72.39,123.18 73.03,123.81 76.2,123.81 76.2,123.18 OUT1-2.5
N$56
  Top 0.254: IC1.13 78.11,113.02 79.38,114.29 79.38,122.54 OUT1-2.7
N$57
  Top 0.254: IC1.2 69.22,113.02 67.95,114.29 67.95,121.27 71.12,124.45 OUT1-2.2
N$58  (via drill 0.61)
  Top 0.254: v66.67,120 67.31,119.37 67.31,111.11 71.12,111.11 71.75,110.48 71.75,106.67 70.48,105.4 IC1.5
  Bottom 0.254: v66.67,120 70.48,123.81 71.75,123.81 73.03,125.08 OUT1-2.4
N$59  (via drill 0.61)
  Top 0.254: v66.04,103.49 v66.04,114.92
  Bottom 0.254: v66.04,103.49 71.12,103.49 72.39,102.22 76.2,102.22 IC1.9 | v66.04,114.92 72.39,121.27 74.3,121.27 74.93,121.91 74.93,125.08 75.56,125.08 OUT1-2.6
N$60
  Top 0.254: IC1.12 76.84,110.48 74.93,112.38 74.93,119.37 77.47,121.91 77.47,123.18 78.74,124.45 OUT1-2.8
N$61  (via drill 0.61)
  Top 0.254: v124.46,111.11 124.46,121.91 OUT5-6.3
  Bottom 0.254: v124.46,111.11 121.28,107.94 IC5.4
N$62
  Top 0.254: IC2.10 89.53,105.4 88.27,106.67 88.27,107.94 88.9,108.57 86.36,111.11 86.36,121.91 OUT1-2.13
N$63
  Top 0.254: IC2.4 83.19,107.94 85.09,109.84 85.09,120.64 83.82,121.91 OUT1-2.11
N$64
  Top 0.254: IC2.1 81.92,115.56 81.28,116.19 81.28,121.91 OUT1-2.9
N$65
  Top 0.254: IC2.2 81.92,113.02 80.01,114.92 80.01,123.18 81.28,124.45 OUT1-2.10
N$66
  Top 0.254: IC2.5 83.19,105.4 85.72,107.94 85.72,121.27 85.09,121.91 85.09,123.18 83.82,124.45 OUT1-2.12
N$67
  Top 0.254: IC2.9 90.81,102.86 92.08,104.12 92.08,123.81 89.53,126.35 86.36,126.35 86.36,125.72 OUT1-2.14
N$68
  Top 0.254: IC2.12 89.53,110.48 87,113.02 87,121.27 87.63,121.91 87.63,123.18 88.9,124.45 OUT1-2.16
N$69
  Bottom 0.254: A5.R2 29.85,92.7 30.48,93.33 41.28,93.33 41.91,92.7 A9.R2
N$70
  Bottom 0.254: A5.S1 39.37,88.25 40.01,87.62 50.8,87.62 51.44,88.25 A9.S1
N$71
  Bottom 0.254: A5.S2 33.02,89.52 33.66,90.16 44.45,90.16 45.09,89.52 A9.S2
N$72
  Bottom 0.254: A5.T1 36.2,85.08 36.83,84.44 47.62,84.44 48.26,85.08 A9.T1
N$73
  Bottom 0.254: A5.T2 29.85,86.35 30.48,86.98 41.28,86.98 41.91,86.35 A9.T2
N$74
  Bottom 0.254: A5.U1 39.37,81.9 40.01,81.27 50.8,81.27 51.44,81.9 A9.U1
N$75
  Bottom 0.254: A5.U2 33.02,83.17 33.66,83.81 44.45,83.81 45.09,83.17 A9.U2
N$76
  Bottom 0.254: A5.V1 36.2,78.73 36.83,78.09 47.62,78.09 48.26,78.73 A9.V1
N$81
  Bottom 0.254: A5.V2 29.85,80 30.48,80.63 41.28,80.63 41.91,80 A9.V2
N$82
  Bottom 0.254: A5.A1 39.37,132.7 40.01,132.06 50.8,132.06 51.44,132.7 A9.A1
N$83
  Bottom 0.254: A5.A2 33.02,133.97 33.66,134.6 44.45,134.6 45.09,133.97 A9.A2
N$84
  Bottom 0.254: A5.B1 36.2,129.53 36.83,128.89 47.62,128.89 48.26,129.53 A9.B1
N$85
  Bottom 0.254: A5.B2 29.85,130.79 30.48,131.43 41.28,131.43 41.91,130.79 A9.B2
N$86
  Bottom 0.254: A5.C1 39.37,126.35 40.01,125.72 50.8,125.72 51.44,126.35 A9.C1
N$87
  Bottom 0.254: A5.C2 33.02,127.62 33.66,128.25 44.45,128.25 45.09,127.62 A9.C2
N$88
  Bottom 0.254: A5.D1 36.2,123.18 36.83,122.54 47.62,122.54 48.26,123.18 A9.D1
N$89
  Bottom 0.254: A5.D2 29.85,124.45 30.48,125.08 41.28,125.08 41.91,124.45 A9.D2
N$90
  Bottom 0.254: A5.E1 39.37,120 40.01,119.37 50.8,119.37 51.44,120 A9.E1
N$91
  Bottom 0.254: A5.E2 33.02,121.27 33.66,121.91 44.45,121.91 45.09,121.27 A9.E2
N$92
  Bottom 0.254: A5.F1 36.2,116.83 36.83,116.19 47.62,116.19 48.26,116.83 A9.F1
N$93
  Bottom 0.254: A5.F2 29.85,118.1 30.48,118.73 41.28,118.73 41.91,118.1 A9.F2
N$95
  Bottom 0.254: A5.H1 39.37,113.65 40.01,113.02 50.8,113.02 51.44,113.65 A9.H1
N$96
  Bottom 0.254: A5.H2 33.02,114.92 33.66,115.56 44.45,115.56 45.09,114.92 A9.H2
N$97
  Bottom 0.254: A5.J1 36.2,110.48 36.83,109.84 47.62,109.84 48.26,110.48 A9.J1
N$98
  Bottom 0.254: A5.J2 29.85,111.75 30.48,112.38 41.28,112.38 41.91,111.75 A9.J2
N$99
  Bottom 0.254: A5.K1 39.37,107.3 40.01,106.67 50.8,106.67 51.44,107.3 A9.K1
N$100
  Bottom 0.254: A5.K2 33.02,108.57 33.66,109.21 44.45,109.21 45.09,108.57 A9.K2
N$113
  Bottom 0.254: A6.L1 10.8,104.12 11.43,103.49 22.23,103.49 22.86,104.12 A7.L1
N$114
  Bottom 0.254: A6.L2 4.45,105.4 5.08,106.03 15.88,106.03 16.51,105.4 A7.L2
N$115
  Bottom 0.254: A6.M1 13.97,100.95 14.61,100.32 25.4,100.32 26.04,100.95 A7.M1
N$116
  Bottom 0.254: A6.M2 7.62,102.22 8.26,102.86 19.05,102.86 19.69,102.22 A7.M2
N$117
  Bottom 0.254: A6.N1 10.8,97.78 11.43,97.14 22.23,97.14 22.86,97.78 A7.N1
N$118
  Bottom 0.254: A6.N2 4.45,99.05 5.08,99.68 15.88,99.68 16.51,99.05 A7.N2
N$119
  Bottom 0.254: A6.P1 13.97,94.6 14.61,93.97 25.4,93.97 26.04,94.6 A7.P1
N$120
  Bottom 0.254: A6.P2 7.62,95.87 8.26,96.51 19.05,96.51 19.69,95.87 A7.P2
N$121
  Bottom 0.254: A6.R1 10.8,91.43 11.43,90.79 22.23,90.79 22.86,91.43 A7.R1
N$122
  Bottom 0.254: A6.R2 4.45,92.7 5.08,93.33 15.88,93.33 16.51,92.7 A7.R2
N$123
  Bottom 0.254: A6.S1 13.97,88.25 14.61,87.62 25.4,87.62 26.04,88.25 A7.S1
N$137
  Bottom 0.254: A6.S2 7.62,89.52 8.26,90.16 19.05,90.16 19.69,89.52 A7.S2
N$138
  Top 0.254: IC5.13 128.91,113.02 130.18,114.29 130.18,122.54 OUT5-6.7
N$139
  Top 0.254: IC2.13 89.53,113.02 87.63,114.92 87.63,120.64 88.9,121.91 OUT1-2.15
N$140
  Top 0.254: IC5.2 120.02,113.02 118.11,114.92 118.11,121.91 121.28,125.08 OUT5-6.2
N$141  (via drill 0.61)
  Top 0.254: v118.75,111.11 118.75,106.67 120.02,105.4 IC5.5 | v119.38,117.46 120.02,118.1 120.02,122.54 121.28,123.81 123.83,123.81 123.83,125.08 OUT5-6.4
  Bottom 0.254: v118.75,111.11 118.75,117.46 v119.38,117.46
N$142
  Top 0.254: IC5.9 128.91,102.86 131.44,105.4 131.44,107.94 132.08,108.57 135.25,108.57 135.25,115.56 134.62,116.19 133.35,116.19 133.35,125.72 132.72,126.35 127,126.35 127,125.72 OUT5-6.6
N$143
  Top 0.254: IC5.12 127.64,110.48 125.73,112.38 125.73,119.37 128.27,121.91 128.27,123.18 129.54,124.45 OUT5-6.8
N$144
  Top 0.254: IC6.10 141.61,105.4 143.51,107.3 143.51,123.18 140.34,126.35 135.89,126.35 135.89,124.45 137.16,123.18 OUT5-6.13
N$145
  Top 0.254: IC6.4 134.62,107.3 135.89,107.3 135.89,120.64 134.62,121.91 OUT5-6.11
N$146
  Top 0.254: IC6.1 132.72,115.56 132.08,116.19 132.08,121.91 OUT5-6.9
N$147
  Top 0.254: IC6.2 132.72,113.02 130.81,114.92 130.81,123.18 132.08,124.45 OUT5-6.10
N$148
  Top 0.254: IC6.9 140.34,102.86 137.8,105.4 137.8,121.27 138.43,121.91 138.43,123.18 137.16,124.45 OUT5-6.14
N$149
  Top 0.254: IC6.12 141.61,110.48 142.88,111.75 142.88,121.27 139.7,124.45 OUT5-6.16
N$150
  Top 0.254: IC5.1 120.65,115.56 120.65,120.64 121.92,121.91 OUT5-6.1
N$151
  Bottom 0.254: IC5.10 128.91,105.4 131.44,107.94 131.44,113.65 137.16,113.65 139.7,116.19 140.34,116.19 140.97,116.83 140.97,121.27 128.91,121.27 127.64,122.54 OUT5-6.5
N$152
  Top 0.254: IC6.5 134.62,104.76 136.53,106.67 136.53,121.27 135.89,121.91 135.89,123.18 134.62,124.45 OUT5-6.12
N$153
  Top 0.254: IC6.13 140.34,113.02 138.43,114.92 138.43,120.64 139.7,121.91 OUT5-6.15
N$154
  Top 0.254: IC3.4 95.89,107.94 99.06,111.11 99.06,121.91 OUT3-4.3
N$155
  Top 0.254: IC3.13 103.5,113.02 104.78,114.29 104.78,122.54 OUT3-4.7
N$156
  Top 0.254: IC3.2 94.62,113.02 93.34,114.29 93.34,121.27 96.52,124.45 OUT3-4.2
N$157
  Top 0.254: IC3.5 94.62,105.4 92.71,107.3 92.71,123.18 95.89,126.35 99.06,126.35 99.06,125.72 OUT3-4.4
N$158
  Top 0.254: IC3.9 103.5,102.86 104.78,104.12 104.78,110.48 104.14,111.11 101.6,111.11 100.33,112.38 100.33,119.37 102.87,121.91 102.87,123.18 101.6,124.45 OUT3-4.6
N$159
  Top 0.254: IC3.12 101.6,109.84 99.69,111.75 99.69,121.27 100.33,121.91 100.33,125.72 100.97,126.35 104.14,126.35 104.14,125.72 OUT3-4.8
N$160
  Top 0.254: IC4.10 114.94,105.4 113.66,106.67 113.66,110.48 111.76,112.38 111.76,121.91 OUT3-4.13
N$161
  Top 0.254: IC4.4 108.59,107.94 110.49,109.84 110.49,120.64 109.22,121.91 OUT3-4.11
N$162
  Top 0.254: IC4.1 107.31,115.56 106.68,116.19 106.68,121.91 OUT3-4.9
N$163
  Top 0.254: IC4.2 107.31,113.02 105.41,114.92 105.41,123.18 106.68,124.45 OUT3-4.10
N$164
  Top 0.254: IC4.9 114.94,102.86 113.03,104.76 113.03,109.84 111.12,111.75 111.12,121.27 110.49,121.91 110.49,123.18 111.76,124.45 OUT3-4.14
N$165
  Top 0.254: IC4.12 114.94,110.48 113.03,112.38 113.03,123.18 114.3,124.45 OUT3-4.16
N$166
  Top 0.254: IC3.1 95.25,115.56 95.25,120.64 96.52,121.91 OUT3-4.1
N$167  (via drill 0.61)
  Top 0.254: v99.69,110.48 100.97,109.21 100.97,106.67 102.23,105.4 IC3.10 | v97.79,112.38 v97.79,119.37
  Bottom 0.254: v99.69,110.48 v97.79,112.38 | v97.79,119.37 100.97,122.54 OUT3-4.5
N$168
  Top 0.254: IC4.5 107.31,105.4 106.05,106.67 106.05,110.48 106.68,111.11 109.86,111.11 109.86,115.56 109.22,116.19 107.95,116.19 107.95,123.18 109.22,124.45 OUT3-4.12
N$169
  Top 0.254: IC4.13 116.2,113.02 117.47,114.29 117.47,118.73 114.3,121.91 OUT3-4.15
N$170  (via drill 0.61)
  Top 0.254: v126.36,67.93 127,68.57 127,74.28 127.64,74.92 127.64,81.9 OUT7-8.3
  Bottom 0.254: v126.36,67.93 125.73,67.93 124.46,66.66 IC7.4
N$171
  Top 0.254: IC7.13 131.44,72.38 132.72,73.65 132.72,81.9 OUT7-8.7
N$172  (via drill 0.61)
  Top 0.254: v126.36,74.92 125.73,75.55 125.73,82.54 124.46,83.81 OUT7-8.2
  Bottom 0.254: v126.36,74.92 123.83,72.38 IC7.2
N$173
  Top 0.254: IC7.5 122.56,64.76 121.28,66.03 121.28,77.46 121.92,78.09 121.92,84.44 121.28,85.08 126.36,90.16 127.64,90.16 127.64,84.44 OUT7-8.4
N$174  (via drill 0.61)
  Top 0.254: v132.72,67.93 132.72,63.48 131.44,62.21 IC7.9
  Bottom 0.254: v132.72,67.93 132.72,69.2 133.99,70.47 137.16,70.47 142.24,75.55 142.88,75.55 143.51,76.19 143.51,80.63 131.44,80.63 130.81,81.27 130.81,83.81 129.54,83.81 OUT7-8.6
N$175
  Top 0.254: IC7.12 130.18,69.84 128.91,71.11 128.91,75.55 128.27,76.19 128.27,85.08 128.91,85.71 132.08,85.71 132.08,85.08 OUT7-8.8
N$176
  Top 0.254: IC8.10 142.24,64.12 139.7,66.66 139.7,78.73 140.34,79.36 140.34,81.9 OUT7-8.13
N$177
  Top 0.254: IC8.4 136.53,67.3 138.43,69.2 138.43,78.73 137.16,80 137.16,81.27 OUT7-8.11
N$178
  Top 0.254: IC8.1 135.25,74.92 134.62,75.55 134.62,81.27 OUT7-8.9
N$179
  Top 0.254: IC8.2 135.25,72.38 133.35,74.28 133.35,82.54 134.62,83.81 OUT7-8.10
N$180
  Bottom 0.254: IC8.9 144.14,62.21 146.69,64.76 146.69,85.71 141.61,85.71 140.34,84.44 OUT7-8.14
N$181
  Bottom 0.254: IC8.12 144.78,69.2 145.42,69.84 146.05,69.84 146.05,83.81 142.24,83.81 OUT7-8.16
N$182
  Top 0.254: IC7.1 123.19,74.92 123.19,80 124.46,81.27 OUT7-8.1
N$183  (via drill 0.61)
  Top 0.254: v138.43,67.93 139.06,68.57 v139.06,79.36 | v129.54,79.36 129.54,81.27 OUT7-8.5
  Bottom 0.254: v138.43,67.93 134.62,67.93 131.44,64.76 IC7.10 | v139.06,79.36 v129.54,79.36
N$184
  Top 0.254: IC8.5 137.16,64.12 140.97,64.12 142.24,62.85 145.42,62.85 145.42,67.3 144.78,67.93 140.34,67.93 140.34,78.09 140.97,78.73 140.97,82.54 140.34,83.17 137.16,83.17 137.16,83.81 OUT7-8.12
N$185
  Top 0.254: IC8.13 142.88,72.38 140.97,74.28 140.97,77.46 142.24,78.73 142.24,81.27 OUT7-8.15
N$186
  Bottom 0.254: A6.T1 10.8,85.08 11.43,84.44 22.23,84.44 22.86,85.08 A7.T1
N$187
  Bottom 0.254: A6.T2 4.45,86.35 5.08,86.98 15.88,86.98 16.51,86.35 A7.T2
N$188
  Bottom 0.254: A6.U1 13.97,81.9 14.61,81.27 25.4,81.27 26.04,81.9 A7.U1
N$189
  Bottom 0.254: A6.U2 7.62,83.17 8.26,83.81 19.05,83.81 19.69,83.17 A7.U2
N$190
  Bottom 0.254: A6.V1 10.8,78.73 11.43,78.09 22.23,78.09 22.86,78.73 A7.V1
N$191
  Bottom 0.254: A6.V2 4.45,80 5.08,80.63 15.88,80.63 16.51,80 A7.V2
N$192
  Bottom 0.254: A6.A1 13.97,132.7 14.61,132.06 25.4,132.06 26.04,132.7 A7.A1
N$193
  Bottom 0.254: A6.A2 7.62,133.97 8.26,134.6 19.05,134.6 19.69,133.97 A7.A2
N$194
  Bottom 0.254: A6.B1 10.8,129.53 11.43,128.89 22.23,128.89 22.86,129.53 A7.B1
N$195
  Bottom 0.254: A6.B2 4.45,130.79 5.08,131.43 15.88,131.43 16.51,130.79 A7.B2
N$196
  Bottom 0.254: A6.C1 13.97,126.35 14.61,125.72 25.4,125.72 26.04,126.35 A7.C1
N$197
  Bottom 0.254: A6.C2 7.62,127.62 8.26,128.25 19.05,128.25 19.69,127.62 A7.C2
N$198
  Bottom 0.254: A6.D1 10.8,123.18 11.43,122.54 22.23,122.54 22.86,123.18 A7.D1
N$199
  Bottom 0.254: A6.D2 4.45,124.45 5.08,125.08 15.88,125.08 16.51,124.45 A7.D2
N$200
  Bottom 0.254: A6.E1 13.97,120 14.61,119.37 25.4,119.37 26.04,120 A7.E1
N$201
  Bottom 0.254: A6.E2 7.62,121.27 8.26,121.91 19.05,121.91 19.69,121.27 A7.E2
N$202
  Bottom 0.254: A6.F1 10.8,116.83 11.43,116.19 22.23,116.19 22.86,116.83 A7.F1
N$203
  Bottom 0.254: A6.F2 4.45,118.1 5.08,118.73 15.88,118.73 16.51,118.1 A7.F2
N$204
  Bottom 0.254: A6.H1 13.97,113.65 14.61,113.02 25.4,113.02 26.04,113.65 A7.H1
N$205
  Bottom 0.254: A6.H2 7.62,114.92 8.26,115.56 19.05,115.56 19.69,114.92 A7.H2
N$206
  Bottom 0.254: A6.J1 10.8,110.48 11.43,109.84 22.23,109.84 22.86,110.48 A7.J1
N$207
  Bottom 0.254: A6.J2 4.45,111.75 5.08,112.38 15.88,112.38 16.51,111.75 A7.J2
N$208
  Bottom 0.254: A6.K1 13.97,107.3 14.61,106.67 25.4,106.67 26.04,107.3 A7.K1
N$209
  Bottom 0.254: A6.K2 7.62,108.57 8.26,109.21 19.05,109.21 19.69,108.57 A7.K2
N$210
  Bottom 0.254: A8.L1 10.8,34.27 11.43,33.64 22.23,33.64 22.86,34.27 A10.L1
N$211
  Bottom 0.254: A8.L2 4.45,35.55 5.08,36.18 15.88,36.18 16.51,35.55 A10.L2
N$212
  Bottom 0.254: A8.M1 13.97,31.1 14.61,30.46 25.4,30.46 26.04,31.1 A10.M1
N$213
  Bottom 0.254: A8.M2 7.62,32.37 8.26,33.01 19.05,33.01 19.69,32.37 A10.M2
N$214
  Bottom 0.254: A8.N1 10.8,27.92 11.43,27.29 22.23,27.29 22.86,27.92 A10.N1
N$215
  Bottom 0.254: A8.N2 4.45,29.2 5.08,29.83 15.88,29.83 16.51,29.2 A10.N2
N$216
  Bottom 0.254: A8.P1 13.97,24.75 14.61,24.11 25.4,24.11 26.04,24.75 A10.P1
N$217
  Bottom 0.254: A8.P2 7.62,26.02 8.26,26.65 19.05,26.65 19.69,26.02 A10.P2
N$218
  Bottom 0.254: A8.R1 10.8,21.57 11.43,20.94 22.23,20.94 22.86,21.57 A10.R1
N$219
  Bottom 0.254: A8.R2 4.45,22.84 5.08,23.48 15.88,23.48 16.51,22.84 A10.R2
N$220
  Bottom 0.254: A8.S1 13.97,18.4 14.61,17.77 25.4,17.77 26.04,18.4 A10.S1
N$221
  Bottom 0.254: A8.S2 7.62,19.67 8.26,20.3 19.05,20.3 19.69,19.67 A10.S2
N$222
  Bottom 0.254: A8.T1 10.8,15.22 11.43,14.59 22.23,14.59 22.86,15.22 A10.T1
N$223
  Bottom 0.254: A8.T2 4.45,16.49 5.08,17.13 15.88,17.13 16.51,16.49 A10.T2
N$224
  Bottom 0.254: A8.U1 13.97,12.05 14.61,11.41 25.4,11.41 26.04,12.05 A10.U1
N$225
  Bottom 0.254: A8.U2 7.62,13.32 8.26,13.95 19.05,13.95 19.69,13.32 A10.U2
N$226
  Bottom 0.254: A8.V1 10.8,8.88 11.43,8.24 22.23,8.24 22.86,8.88 A10.V1
N$227
  Bottom 0.254: A8.V2 4.45,10.14 5.08,10.78 15.88,10.78 16.51,10.14 A10.V2
N$228
  Bottom 0.254: A8.A1 13.97,62.85 14.61,62.21 25.4,62.21 26.04,62.85 A10.A1
N$229
  Bottom 0.254: A8.A2 7.62,64.12 8.26,64.76 19.05,64.76 19.69,64.12 A10.A2
N$230
  Bottom 0.254: A8.B1 10.8,59.68 11.43,59.04 22.23,59.04 22.86,59.68 A10.B1
N$231
  Bottom 0.254: A8.B2 4.45,60.95 5.08,61.58 15.88,61.58 16.51,60.95 A10.B2
N$232
  Bottom 0.254: A8.C1 13.97,56.5 14.61,55.87 25.4,55.87 26.04,56.5 A10.C1
N$233
  Bottom 0.254: A8.C2 7.62,57.77 8.26,58.41 19.05,58.41 19.69,57.77 A10.C2
N$234
  Bottom 0.254: A8.D1 10.8,53.32 11.43,52.69 22.23,52.69 22.86,53.32 A10.D1
N$235
  Bottom 0.254: A8.D2 4.45,54.59 5.08,55.23 15.88,55.23 16.51,54.59 A10.D2
N$236
  Bottom 0.254: A8.E1 13.97,50.15 14.61,49.52 25.4,49.52 26.04,50.15 A10.E1
N$237
  Bottom 0.254: A8.E2 7.62,51.42 8.26,52.05 19.05,52.05 19.69,51.42 A10.E2
N$238
  Bottom 0.254: A8.F1 10.8,46.98 11.43,46.34 22.23,46.34 22.86,46.98 A10.F1
N$239
  Bottom 0.254: A8.F2 4.45,48.24 5.08,48.88 15.88,48.88 16.51,48.24 A10.F2
N$240
  Bottom 0.254: A8.H1 13.97,43.8 14.61,43.16 25.4,43.16 26.04,43.8 A10.H1
N$241
  Bottom 0.254: A8.H2 7.62,45.07 8.26,45.7 19.05,45.7 19.69,45.07 A10.H2
N$242
  Bottom 0.254: A8.J1 10.8,40.62 11.43,39.99 22.23,39.99 22.86,40.62 A10.J1
N$243
  Bottom 0.254: A8.J2 4.45,41.89 5.08,42.53 15.88,42.53 16.51,41.89 A10.J2
N$244
  Bottom 0.254: A8.K1 13.97,37.45 14.61,36.81 25.4,36.81 26.04,37.45 A10.K1
N$245
  Bottom 0.254: A8.K2 7.62,38.72 8.26,39.35 19.05,39.35 19.69,38.72 A10.K2
N$246
  Bottom 0.254: A11.L1 36.2,34.27 36.83,33.64 47.62,33.64 48.26,34.27 A12.L1
N$247
  Bottom 0.254: A11.L2 29.85,35.55 30.48,36.18 41.28,36.18 41.91,35.55 A12.L2
N$248
  Bottom 0.254: A11.M1 39.37,31.1 40.01,30.46 50.8,30.46 51.44,31.1 A12.M1
N$249
  Bottom 0.254: A11.M2 33.02,32.37 33.66,33.01 44.45,33.01 45.09,32.37 A12.M2
N$250
  Bottom 0.254: A11.N1 36.2,27.92 36.83,27.29 47.62,27.29 48.26,27.92 A12.N1
N$251
  Bottom 0.254: A11.N2 29.85,29.2 30.48,29.83 41.28,29.83 41.91,29.2 A12.N2
N$252
  Bottom 0.254: A11.P1 39.37,24.75 40.01,24.11 50.8,24.11 51.44,24.75 A12.P1
N$253
  Bottom 0.254: A11.P2 33.02,26.02 33.66,26.65 44.45,26.65 45.09,26.02 A12.P2
N$254
  Bottom 0.254: A11.R1 36.2,21.57 36.83,20.94 47.62,20.94 48.26,21.57 A12.R1
N$255
  Bottom 0.254: A11.R2 29.85,22.84 30.48,23.48 41.28,23.48 41.91,22.84 A12.R2
N$256
  Bottom 0.254: A11.S1 39.37,18.4 40.01,17.77 50.8,17.77 51.44,18.4 A12.S1
N$257
  Bottom 0.254: A11.S2 33.02,19.67 33.66,20.3 44.45,20.3 45.09,19.67 A12.S2
N$258
  Bottom 0.254: A11.T1 36.2,15.22 36.83,14.59 47.62,14.59 48.26,15.22 A12.T1
N$259
  Bottom 0.254: A11.T2 29.85,16.49 30.48,17.13 41.28,17.13 41.91,16.49 A12.T2
N$260
  Bottom 0.254: A11.U1 39.37,12.05 40.01,11.41 50.8,11.41 51.44,12.05 A12.U1
N$261
  Bottom 0.254: A11.U2 33.02,13.32 33.66,13.95 44.45,13.95 45.09,13.32 A12.U2
N$262
  Bottom 0.254: A11.V1 36.2,8.88 36.83,8.24 47.62,8.24 48.26,8.88 A12.V1
N$263
  Bottom 0.254: A11.V2 29.85,10.14 30.48,10.78 41.28,10.78 41.91,10.14 A12.V2
N$264
  Bottom 0.254: A11.A1 39.37,62.85 40.01,62.21 50.8,62.21 51.44,62.85 A12.A1
N$265
  Bottom 0.254: A11.A2 33.02,64.12 33.66,64.76 44.45,64.76 45.09,64.12 A12.A2
N$266
  Bottom 0.254: A11.B1 36.2,59.68 36.83,59.04 47.62,59.04 48.26,59.68 A12.B1
N$267
  Bottom 0.254: A11.B2 29.85,60.95 30.48,61.58 41.28,61.58 41.91,60.95 A12.B2
N$268
  Bottom 0.254: A11.C1 39.37,56.5 40.01,55.87 50.8,55.87 51.44,56.5 A12.C1
N$269
  Bottom 0.254: A11.C2 33.02,57.77 33.66,58.41 44.45,58.41 45.09,57.77 A12.C2
N$270
  Bottom 0.254: A11.D1 36.2,53.32 36.83,52.69 47.62,52.69 48.26,53.32 A12.D1
N$271
  Bottom 0.254: A11.D2 29.85,54.59 30.48,55.23 41.28,55.23 41.91,54.59 A12.D2
N$272
  Bottom 0.254: A11.E1 39.37,50.15 40.01,49.52 50.8,49.52 51.44,50.15 A12.E1
N$273
  Bottom 0.254: A11.E2 33.02,51.42 33.66,52.05 44.45,52.05 45.09,51.42 A12.E2
N$274
  Bottom 0.254: A11.F1 36.2,46.98 36.83,46.34 47.62,46.34 48.26,46.98 A12.F1
N$275
  Bottom 0.254: A11.F2 29.85,48.24 30.48,48.88 41.28,48.88 41.91,48.24 A12.F2
N$276
  Bottom 0.254: A11.H1 39.37,43.8 40.01,43.16 50.8,43.16 51.44,43.8 A12.H1
N$277
  Bottom 0.254: A11.H2 33.02,45.07 33.66,45.7 44.45,45.7 45.09,45.07 A12.H2
N$278
  Bottom 0.254: A11.J1 36.2,40.62 36.83,39.99 47.62,39.99 48.26,40.62 A12.J1
N$279
  Bottom 0.254: A11.J2 29.85,41.89 30.48,42.53 41.28,42.53 41.91,41.89 A12.J2
N$280
  Bottom 0.254: A11.K1 39.37,37.45 40.01,36.81 50.8,36.81 51.44,37.45 A12.K1
N$281
  Bottom 0.254: A11.K2 33.02,38.72 33.66,39.35 44.45,39.35 45.09,38.72 A12.K2
OA1
  Top 0.254: 67.31,97.14 65.41,97.14 63.5,95.23 63.5,72.38 64.77,72.38 66.04,73.65 66.04,74.28 A1-K1.18 | 67.31,97.14 67.31,95.87 JP1.1 | 67.31,97.14 67.31,107.3 69.22,109.21 IC1.3
OB1
  Top 0.254: A1-K1.17 68.58,76.82 64.77,80.63 64.77,87.62 66.04,88.89 66.04,91.43 67.31,92.7 69.22,92.7 69.22,93.97 JP1.2 69.85,95.87 67.95,97.78 67.95,100.32 69.22,101.59 IC1.6
OB2
  Bottom 0.254: A2-K2.17 68.58,61.58 62.23,67.93 62.23,87.62 69.22,87.62 69.85,88.25 JP2.2
OC
  Top 0.254: IN5-6.1 122.56,5.7 123.83,6.97 140.34,6.97 146.05,12.68 146.05,26.65 143.51,29.2 143.51,30.46 144.14,31.1 OC.1
  Bottom 0.254: IC9.8 123.83,25.38 132.72,25.38 IC9.13 137.16,29.83 142.88,29.83 144.14,31.1 OC.1
OC1  (via drill 0.61)
  Top 0.254: A1-K1.16 71.12,76.82 72.39,78.09 72.39,86.35 73.66,87.62 73.66,91.43 72.39,92.7 72.39,93.33 JP1.3 72.39,95.87 v72.39,99.68
  Bottom 0.254: v72.39,99.68 76.2,99.68 IC1.8
OD1  (via drill 0.61)
  Top 0.254: v69.85,80.63 69.85,86.35 68.58,87.62 v68.58,91.43 | IC1.11 76.84,106.67 75.56,105.4 75.56,95.23 JP1.4
  Bottom 0.254: v69.85,80.63 73.66,76.82 A1-K1.15 | v68.58,91.43 69.85,92.7 74.3,92.7 74.93,93.33 JP1.4
OD2  (via drill 0.61)
  Top 0.254: A2-K2.15 73.66,61.58 72.39,62.85 72.39,76.82 v73.66,78.09 74.3,78.73 74.3,80.63 74.93,81.27 74.93,88.25 JP2.4 | v119.38,78.09 119.38,86.35 118.11,87.62 118.11,99.68 120.02,101.59 IC5.6
  Bottom 0.254: v73.66,78.09 87.63,78.09 88.9,76.82 90.17,78.09 v119.38,78.09
OE1  (via drill 0.61)
  Top 0.254: v64.77,73.65 64.14,74.28 64.14,88.25 65.41,89.52 v65.41,95.87 | IC2.3 81.92,109.21 80.01,107.3 80.01,100.95 79.38,100.32 79.38,97.78 77.47,95.87 JP1.5
  Bottom 0.254: v64.77,73.65 74.3,73.65 75.56,74.92 A1-K1.14 | v65.41,95.87 66.04,96.51 76.84,96.51 77.47,95.87 JP1.5
OE2  (via drill 0.61)
  Top 0.254: v74.3,103.49 73.66,102.86 73.66,92.7 74.93,91.43 77.47,91.43 77.47,90.79 JP2.5
  Bottom 0.254: A2-K2.14 75.56,59.68 74.3,58.41 70.48,58.41 69.85,59.04 69.85,66.03 65.41,66.03 62.87,68.57 62.87,86.98 70.48,86.98 71.12,87.62 71.12,91.43 76.84,91.43 77.47,90.79 JP2.5 | v74.3,103.49 83.82,103.49 86.36,106.03 121.92,106.03 127.64,100.32 IC5.8
OF1
  Top 0.254: A1-K1.13 78.74,76.82 79.38,77.46 79.38,80.63 80.01,81.27 80.01,86.35 78.74,87.62 78.74,92.06 80.01,93.33 JP1.6 80.01,95.87 80.01,99.68 81.92,101.59 IC2.6
OF2  (via drill 0.61)
  Top 0.254: v81.28,80 80.01,78.73 80.01,62.85 78.74,61.58 A2-K2.13 | v123.19,121.27 123.19,111.11 127,107.3 IC5.11 | v67.31,123.18 67.31,121.91 64.77,119.37 64.77,100.95 v66.04,99.68
  Bottom 0.254: v81.28,80 82.55,81.27 82.55,85.71 81.92,85.71 80.01,87.62 80.01,88.25 JP2.6 80.01,90.79 78.74,90.79 78.74,96.51 78.11,97.14 68.58,97.14 v66.04,99.68 | v123.19,121.27 123.19,126.35 70.48,126.35 v67.31,123.18
OH1  (via drill 0.61)
  Top 0.254: A1-K1.12 81.28,76.82 82.55,78.09 82.55,86.35 81.28,87.62 81.28,92.06 82.55,93.33 JP1.7 | v88.9,97.14 88.9,98.41 89.53,99.05 IC2.8
  Bottom 0.254: v88.9,97.14 88.27,96.51 83.19,96.51 82.55,95.87 JP1.7
OH2  (via drill 0.61)
  Top 0.254: v82.55,72.38 82.55,62.85 81.28,61.58 A2-K2.12 | v123.19,96.51 123.19,106.03 129.54,106.03 130.18,106.67 130.18,107.94 132.08,109.84 IC6.3 | v113.66,82.54 v113.66,94.6 | v100.33,72.38 v100.33,82.54
  Bottom 0.254: JP2.7 82.55,88.25 83.82,86.98 87,86.98 88.27,85.71 89.53,85.71 90.81,84.44 93.98,84.44 95.89,82.54 v100.33,82.54 v113.66,82.54 | v123.19,96.51 121.28,94.6 v113.66,94.6 | v100.33,72.38 99.69,73.01 83.19,73.01 v82.55,72.38
OJ1  (via drill 0.61)
  Top 0.254: A1-K1.11 83.82,76.82 85.09,78.09 85.09,86.35 83.82,87.62 83.82,92.06 85.09,93.33 JP1.8 85.09,95.87 85.09,106.03 v85.72,106.67
  Bottom 0.254: v85.72,106.67 88.27,106.67 88.9,107.3 IC2.11
OJ2  (via drill 0.61)
  Top 0.254: v90.17,62.85 89.53,63.48 89.53,76.82 91.44,78.73 91.44,83.81 v88.27,86.98 | v121.92,88.25 121.92,90.79 132.72,101.59 IC6.6 | v103.5,86.98 102.87,86.35 102.87,71.74 100.33,69.2 100.33,66.66 v97.79,64.12
  Bottom 0.254: v88.27,86.98 87.63,87.62 85.72,87.62 85.09,88.25 JP2.8 | A2-K2.11 84.45,60.95 86.36,62.85 v90.17,62.85 91.44,64.12 v97.79,64.12 | v121.92,88.25 120.65,86.98 v103.5,86.98
OK1  (via drill 0.61)
  Top 0.254: A1-K1.10 86.36,76.82 87.63,78.09 87.63,86.35 86.36,87.62 86.36,92.06 87.63,93.33 JP1.9 87.63,95.87 v87.63,108.57
  Bottom 0.254: v87.63,108.57 92.71,108.57 93.98,109.84 IC3.3
OK2  (via drill 0.61)
  Top 0.254: v97.79,66.03 v97.79,83.81
  Bottom 0.254: v97.79,66.03 82.55,66.03 82.55,59.04 83.19,58.41 84.45,58.41 85.72,59.68 A2-K2.10 | v97.79,83.81 95.89,85.71 90.81,85.71 88.27,88.25 87.63,88.25 JP2.9 87.63,90.79 88.9,92.06 111.12,92.06 112.4,93.33 133.35,93.33 139.7,99.68 IC6.8
OL1
  Top 0.254: L1-V1.18 91.44,76.82 92.08,77.46 92.08,85.71 90.81,85.71 88.9,87.62 88.9,92.06 90.17,93.33 JP1.10 90.17,95.87 90.17,97.14 94.62,101.59 IC3.6
OL2  (via drill 0.61)
  Top 0.254: v88.9,78.73 88.9,71.74 88.27,71.11 88.27,63.48 90.81,60.95 L2-V2.18 | v120.65,80 120.65,92.7 124.46,96.51 v124.46,104.76 | v91.44,96.51 91.44,92.06 90.17,90.79 JP2.10
  Bottom 0.254: v88.9,78.73 118.11,78.73 119.38,80 v120.65,80 | v124.46,104.76 125.73,103.49 135.25,103.49 | 135.25,103.49 135.89,103.49 139.7,107.3 IC6.11 | v91.44,96.51 92.71,97.78 133.99,97.78 135.25,99.05 135.25,103.49
OM1  (via drill 0.61)
  Top 0.254: v93.98,81.27 93.98,76.82 L1-V1.17 | v116.84,81.27 116.2,81.9 116.2,86.98 114.94,88.25 114.94,95.87 111.76,99.05 v111.76,99.68 | v99.06,96.51 101.6,99.05 101.6,99.68 IC3.8
  Bottom 0.254: v93.98,81.27 95.25,81.27 v116.84,81.27 | v111.76,99.68 110.49,100.95 105.41,100.95 104.14,99.68 IC3.8 | v99.06,96.51 93.34,96.51 92.71,95.87 JP1.11
OM2  (via drill 0.61)
  Top 0.254: v92.71,71.74 92.71,66.66 93.34,66.03 93.34,62.21 93.98,61.58 L2-V2.17 | v116.2,88.25 118.11,86.35 v118.11,72.38
  Bottom 0.254: v92.71,71.74 93.34,71.11 112.4,71.11 113.66,72.38 v118.11,72.38 118.75,72.38 121.92,69.2 IC7.3 | v116.2,88.25 115.57,87.62 106.68,87.62 106.68,91.43 93.34,91.43 92.71,90.79 JP2.11
ON1  (via drill 0.61)
  Top 0.254: L1-V1.16 96.52,76.82 96.52,92.06 95.25,93.33 JP1.12 95.25,95.87 97.16,97.78 97.16,106.67 v97.79,107.3
  Bottom 0.254: v97.79,107.3 101.6,107.3 IC3.11
ON2
  Top 0.254: JP2.12 95.25,88.25 95.25,66.66 95.89,66.03 95.89,60.95 L2-V2.16
  Bottom 0.254: L2-V2.16 97.16,59.68 98.43,58.41 117.47,58.41 120.65,61.58 121.92,61.58 IC7.6
OP1  (via drill 0.61)
  Top 0.254: L1-V1.15 99.06,76.82 99.06,92.06 97.79,93.33 JP1.13 97.79,95.87 97.79,96.51 99.06,97.78 99.06,107.94 v99.69,108.57
  Bottom 0.254: v99.69,108.57 105.41,108.57 106.68,109.84 IC4.3
OP2  (via drill 0.61)
  Top 0.254: v99.06,63.48 99.06,61.58 L2-V2.15 | v91.44,62.85 90.81,63.48 90.81,66.03 90.17,66.66 90.17,71.74 92.71,74.28 v92.71,86.98 | v130.81,50.78 130.81,58.41 IC7.8 | v118.75,50.78 118.11,51.42 v118.11,65.39
  Bottom 0.254: v91.44,62.85 98.43,62.85 v99.06,63.48 99.69,63.48 101.6,65.39 v118.11,65.39 | v92.71,86.98 93.34,87.62 97.16,87.62 97.79,88.25 JP2.13 | v118.75,50.78 v130.81,50.78
OR1
  Top 0.254: L1-V1.14 101.6,76.82 101.6,92.06 100.33,93.33 JP1.14 100.33,95.87 100.33,96.51 102.23,96.51 107.31,101.59 IC4.6
OR2  (via drill 0.61)
  Top 0.254: v100.33,86.35 100.33,88.25 JP2.14 | v114.94,85.08 115.57,84.44 v115.57,64.12
  Bottom 0.254: L2-V2.14 102.23,60.95 105.41,64.12 v115.57,64.12 120.65,64.12 121.92,65.39 128.27,65.39 129.54,66.66 IC7.11 | v100.33,86.35 101.6,85.08 v114.94,85.08
OS1  (via drill 0.61)
  Top 0.254: L1-V1.13 104.14,76.82 104.78,77.46 104.78,86.98 104.14,87.62 104.14,92.06 102.87,93.33 JP1.15 | v115.57,96.51 115.57,99.05 IC4.8
  Bottom 0.254: v115.57,96.51 103.5,96.51 102.87,95.87 JP1.15
OS2  (via drill 0.61)
  Top 0.254: v107.95,83.81 107.95,74.28 108.59,73.65 108.59,72.38 107.95,71.74 107.95,58.41 106.05,58.41 104.78,59.68 L2-V2.13 | v135.89,85.71 135.89,75.55 137.16,75.55 137.8,74.92 137.8,71.11 136.53,69.84 IC8.3
  Bottom 0.254: v107.95,83.81 107.31,84.44 100.97,84.44 99.06,86.35 99.06,87.62 100.97,87.62 | 100.97,87.62 102.23,87.62 102.87,88.25 JP2.15 | v135.89,85.71 135.25,86.35 104.14,86.35 103.5,85.71 102.87,85.71 100.97,87.62
OT2  (via drill 0.61)
  Top 0.254: 105.41,87.62 105.41,88.25 JP2.16 | 105.41,87.62 105.41,62.85 106.68,61.58 L2-V2.12 | v122.56,85.08 v126.36,88.89 | 105.41,87.62 v109.22,83.81
  Bottom 0.254: v126.36,88.89 135.89,88.89 137.8,86.98 147.32,86.98 147.32,62.85 144.78,60.31 138.43,60.31 137.16,61.58 IC8.6 | v122.56,85.08 121.28,83.81 v109.22,83.81
OU1  (via drill 0.61)
  Top 0.254: L1-V1.11 109.22,76.82 110.49,78.09 110.49,86.35 109.22,87.62 109.22,92.06 107.95,93.33 JP1.17 107.95,95.87 109.86,97.78 109.86,106.67 v110.49,107.3
  Bottom 0.254: v110.49,107.3 114.3,107.3 IC4.11
OU2  (via drill 0.61)
  Top 0.254: v112.4,92.06 112.4,82.54 114.94,80 114.94,71.11 114.3,70.47 114.3,63.48 v114.94,62.85 114.94,53.32 v116.84,51.42
  Bottom 0.254: v114.94,62.85 111.76,62.85 109.86,60.95 L2-V2.11 | v112.4,92.06 111.76,91.43 108.59,91.43 107.95,90.79 JP2.17 | v116.84,51.42 117.47,52.05 130.81,52.05 132.08,50.78 142.88,50.78 142.88,58.41 IC8.8
OV1  (via drill 0.61)
  Top 0.254: L1-V1.10 111.76,76.82 111.76,91.43 110.49,92.7 110.49,93.33 JP1.18 110.49,95.87 110.49,99.68 111.76,100.95 v111.76,108.57
  Bottom 0.254: v111.76,108.57 118.11,108.57 119.38,109.84 IC5.3
OV2
  Bottom 0.254: L2-V2.10 112.4,60.95 113.03,61.58 119.38,61.58 120.65,62.85 138.43,62.85 142.24,66.66 IC8.11 142.88,67.3 141.61,67.3 141.61,69.84 142.24,70.47 145.42,70.47 145.42,80.63 142.88,83.17 138.43,83.17 138.43,85.08 136.53,86.98 127,86.98 124.46,89.52 111.12,89.52 JP2.18
P1  (via drill 0.61)
  Top 0.254: v100.33,65.39 100.33,56.5 97.79,53.96 97.79,32.37 JP3.13 | v139.7,52.05 139.7,44.44 SIDE1.30 | v116.84,66.66 v116.84,52.69
  Bottom 0.254: v100.33,65.39 99.69,66.03 | 99.69,66.03 99.06,66.66 L1-V1.4 | IN1-2.10 80.65,8.24 73.66,15.22 70.48,15.22 63.5,22.21 63.5,29.2 68.58,29.2 68.58,34.27 80.01,34.27 81.28,33.01 97.16,33.01 97.79,32.37 JP3.13 | v139.7,52.05 139.06,52.69 v116.84,52.69 | v116.84,66.66 116.2,66.03 99.69,66.03
P2  (via drill 0.61)
  Top 0.254: L2-V2.4 99.06,51.42 99.06,29.2 97.79,27.92 97.79,27.29 JP4.13 97.79,24.75 v97.79,3.16 | v113.03,10.14 113.03,7.6 111.76,6.33 IN3-4.13 111.12,5.7 v108.59,3.16
  Bottom 0.254: v113.03,10.14 115.57,12.68 128.27,12.68 130.81,15.22 130.81,18.4 131.44,18.4 SIDE2.24 | v97.79,3.16 v108.59,3.16
PIA-B5  (via drill 0.61)
  Top 0.254: v128.27,69.2 128.27,38.72 127,37.45 IC9.5 | v116.84,71.11 v116.84,80
  Bottom 0.254: v116.84,80 93.34,80 | v116.84,71.11 120.02,67.93 124.46,67.93 125.73,69.2 v128.27,69.2 | v116.84,80 93.34,80 | CORE-IO.18 86.36,83.17 90.17,83.17 93.34,80 | v116.84,80 93.34,80 | v116.84,80 93.34,80
PIA-B7  (via drill 0.61)
  Top 0.254: 135.89,34.27 136.53,34.27 IC9.1 | 135.89,34.27 135.25,34.27 IC9.2 | v125.73,100.95 130.81,100.95 130.81,102.22 132.08,103.49 138.43,103.49 138.43,98.41 145.42,91.43 145.42,68.57 146.05,67.93 v146.05,52.69 | v135.89,47.61 135.89,34.27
